VERSION 5.7 ;
  NOWIREEXTENSIONATPIN ON ;
  DIVIDERCHAR "/" ;
  BUSBITCHARS "[]" ;
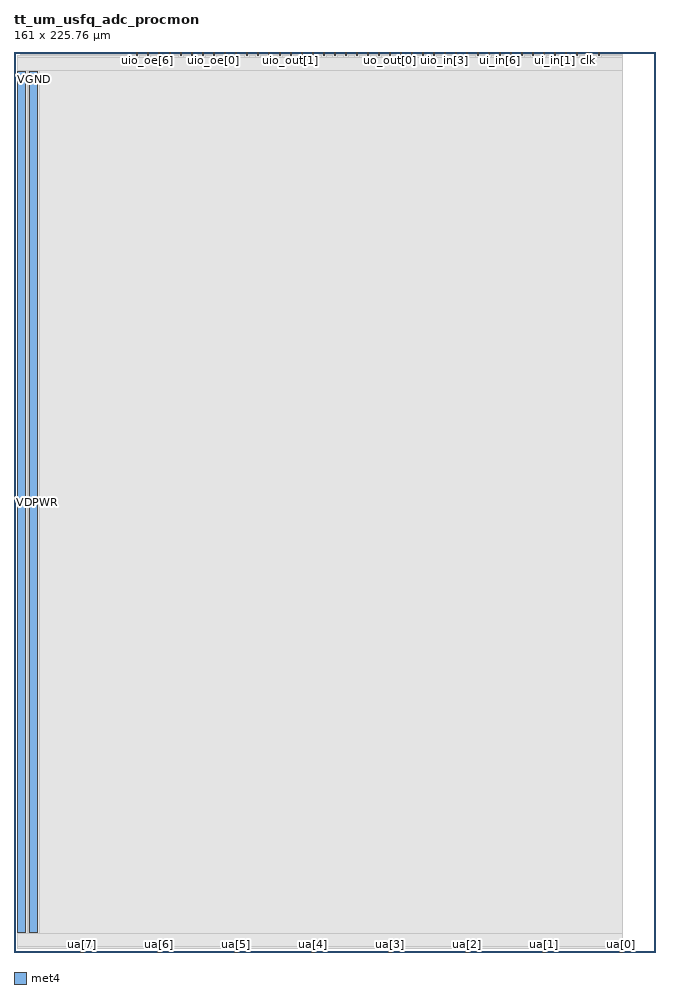
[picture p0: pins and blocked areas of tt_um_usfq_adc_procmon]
MACRO tt_um_usfq_adc_procmon
  CLASS BLOCK ;
  FOREIGN tt_um_usfq_adc_procmon ;
  ORIGIN 0.000 0.000 ;
  SIZE 161.000 BY 225.760 ;
  PIN VGND
    USE GROUND ;
    PORT
      LAYER met4 ;
        RECT 4.000 5.000 6.000 220.760 ;
    END
  END VGND
  PIN VDPWR
    USE POWER ;
    PORT
      LAYER met4 ;
        RECT 1.000 5.000 3.000 220.760 ;
    END
  END VDPWR
  PIN uo_out[7]
    ANTENNADIFFAREA 0.222600 ;
    PORT
      LAYER met4 ;
        RECT 74.830 224.760 75.130 225.760 ;
    END
  END uo_out[7]
  PIN uo_out[6]
    ANTENNADIFFAREA 0.222600 ;
    PORT
      LAYER met4 ;
        RECT 77.590 224.760 77.890 225.760 ;
    END
  END uo_out[6]
  PIN uo_out[5]
    ANTENNADIFFAREA 0.222600 ;
    PORT
      LAYER met4 ;
        RECT 80.350 224.760 80.650 225.760 ;
    END
  END uo_out[5]
  PIN uo_out[4]
    ANTENNADIFFAREA 0.222600 ;
    PORT
      LAYER met4 ;
        RECT 83.110 224.760 83.410 225.760 ;
    END
  END uo_out[4]
  PIN uo_out[3]
    ANTENNADIFFAREA 0.222600 ;
    PORT
      LAYER met4 ;
        RECT 85.870 224.760 86.170 225.760 ;
    END
  END uo_out[3]
  PIN uo_out[2]
    ANTENNADIFFAREA 0.222600 ;
    PORT
      LAYER met4 ;
        RECT 88.630 224.760 88.930 225.760 ;
    END
  END uo_out[2]
  PIN uo_out[1]
    PORT
      LAYER met4 ;
        RECT 91.390 224.760 91.690 225.760 ;
    END
  END uo_out[1]
  PIN uo_out[0]
    PORT
      LAYER met4 ;
        RECT 94.150 224.760 94.450 225.760 ;
    END
  END uo_out[0]
  PIN uio_out[7]
    ANTENNADIFFAREA 4.233600 ;
    PORT
      LAYER met4 ;
        RECT 52.750 224.760 53.050 225.760 ;
    END
  END uio_out[7]
  PIN uio_out[6]
    ANTENNADIFFAREA 4.233600 ;
    PORT
      LAYER met4 ;
        RECT 55.510 224.760 55.810 225.760 ;
    END
  END uio_out[6]
  PIN uio_out[5]
    ANTENNADIFFAREA 4.233600 ;
    PORT
      LAYER met4 ;
        RECT 58.270 224.760 58.570 225.760 ;
    END
  END uio_out[5]
  PIN uio_out[4]
    ANTENNADIFFAREA 4.233600 ;
    PORT
      LAYER met4 ;
        RECT 61.030 224.760 61.330 225.760 ;
    END
  END uio_out[4]
  PIN uio_out[3]
    ANTENNADIFFAREA 4.233600 ;
    PORT
      LAYER met4 ;
        RECT 63.790 224.760 64.090 225.760 ;
    END
  END uio_out[3]
  PIN uio_out[2]
    ANTENNADIFFAREA 4.233600 ;
    PORT
      LAYER met4 ;
        RECT 66.550 224.760 66.850 225.760 ;
    END
  END uio_out[2]
  PIN uio_out[1]
    ANTENNADIFFAREA 4.936500 ;
    PORT
      LAYER met4 ;
        RECT 69.310 224.760 69.610 225.760 ;
    END
  END uio_out[1]
  PIN uio_out[0]
    ANTENNADIFFAREA 4.233600 ;
    PORT
      LAYER met4 ;
        RECT 72.070 224.760 72.370 225.760 ;
    END
  END uio_out[0]
  PIN uio_oe[7]
    ANTENNAGATEAREA 32.830997 ;
    ANTENNADIFFAREA 174.069748 ;
    PORT
      LAYER met4 ;
        RECT 30.670 224.760 30.970 225.760 ;
    END
  END uio_oe[7]
  PIN uio_oe[6]
    ANTENNAGATEAREA 32.830997 ;
    ANTENNADIFFAREA 174.069748 ;
    PORT
      LAYER met4 ;
        RECT 33.430 224.760 33.730 225.760 ;
    END
  END uio_oe[6]
  PIN uio_oe[5]
    ANTENNAGATEAREA 32.830997 ;
    ANTENNADIFFAREA 174.069748 ;
    PORT
      LAYER met4 ;
        RECT 36.190 224.760 36.490 225.760 ;
    END
  END uio_oe[5]
  PIN uio_oe[4]
    ANTENNAGATEAREA 32.830997 ;
    ANTENNADIFFAREA 174.069748 ;
    PORT
      LAYER met4 ;
        RECT 38.950 224.760 39.250 225.760 ;
    END
  END uio_oe[4]
  PIN uio_oe[3]
    ANTENNAGATEAREA 32.830997 ;
    ANTENNADIFFAREA 174.069748 ;
    PORT
      LAYER met4 ;
        RECT 41.710 224.760 42.010 225.760 ;
    END
  END uio_oe[3]
  PIN uio_oe[2]
    ANTENNAGATEAREA 32.830997 ;
    ANTENNADIFFAREA 174.069748 ;
    PORT
      LAYER met4 ;
        RECT 44.470 224.760 44.770 225.760 ;
    END
  END uio_oe[2]
  PIN uio_oe[1]
    ANTENNAGATEAREA 32.830997 ;
    ANTENNADIFFAREA 174.069748 ;
    PORT
      LAYER met4 ;
        RECT 47.230 224.760 47.530 225.760 ;
    END
  END uio_oe[1]
  PIN uio_oe[0]
    ANTENNAGATEAREA 32.830997 ;
    ANTENNADIFFAREA 174.069748 ;
    PORT
      LAYER met4 ;
        RECT 49.990 224.760 50.290 225.760 ;
    END
  END uio_oe[0]
  PIN uio_in[7]
    PORT
      LAYER met4 ;
        RECT 96.910 224.760 97.210 225.760 ;
    END
  END uio_in[7]
  PIN uio_in[6]
    PORT
      LAYER met4 ;
        RECT 99.670 224.760 99.970 225.760 ;
    END
  END uio_in[6]
  PIN uio_in[5]
    PORT
      LAYER met4 ;
        RECT 102.430 224.760 102.730 225.760 ;
    END
  END uio_in[5]
  PIN uio_in[4]
    PORT
      LAYER met4 ;
        RECT 105.190 224.760 105.490 225.760 ;
    END
  END uio_in[4]
  PIN uio_in[3]
    PORT
      LAYER met4 ;
        RECT 107.950 224.760 108.250 225.760 ;
    END
  END uio_in[3]
  PIN uio_in[2]
    PORT
      LAYER met4 ;
        RECT 110.710 224.760 111.010 225.760 ;
    END
  END uio_in[2]
  PIN uio_in[1]
    PORT
      LAYER met4 ;
        RECT 113.470 224.760 113.770 225.760 ;
    END
  END uio_in[1]
  PIN uio_in[0]
    PORT
      LAYER met4 ;
        RECT 116.230 224.760 116.530 225.760 ;
    END
  END uio_in[0]
  PIN ui_in[7]
    ANTENNAGATEAREA 1.431000 ;
    PORT
      LAYER met4 ;
        RECT 118.990 224.760 119.290 225.760 ;
    END
  END ui_in[7]
  PIN ui_in[6]
    PORT
      LAYER met4 ;
        RECT 121.750 224.760 122.050 225.760 ;
    END
  END ui_in[6]
  PIN ui_in[5]
    PORT
      LAYER met4 ;
        RECT 124.510 224.760 124.810 225.760 ;
    END
  END ui_in[5]
  PIN ui_in[4]
    PORT
      LAYER met4 ;
        RECT 127.270 224.760 127.570 225.760 ;
    END
  END ui_in[4]
  PIN ui_in[3]
    PORT
      LAYER met4 ;
        RECT 130.030 224.760 130.330 225.760 ;
    END
  END ui_in[3]
  PIN ui_in[2]
    PORT
      LAYER met4 ;
        RECT 132.790 224.760 133.090 225.760 ;
    END
  END ui_in[2]
  PIN ui_in[1]
    PORT
      LAYER met4 ;
        RECT 135.550 224.760 135.850 225.760 ;
    END
  END ui_in[1]
  PIN ui_in[0]
    PORT
      LAYER met4 ;
        RECT 138.310 224.760 138.610 225.760 ;
    END
  END ui_in[0]
  PIN ua[7]
    PORT
      LAYER met4 ;
        RECT 16.570 0.000 17.470 1.000 ;
    END
  END ua[7]
  PIN ua[5]
    PORT
      LAYER met4 ;
        RECT 55.210 0.000 56.110 1.000 ;
    END
  END ua[5]
  PIN ua[4]
    PORT
      LAYER met4 ;
        RECT 74.530 0.000 75.430 1.000 ;
    END
  END ua[4]
  PIN ua[3]
    PORT
      LAYER met4 ;
        RECT 93.850 0.000 94.750 1.000 ;
    END
  END ua[3]
  PIN ua[2]
    PORT
      LAYER met4 ;
        RECT 113.170 0.000 114.070 1.000 ;
    END
  END ua[2]
  PIN ua[1]
    ANTENNAGATEAREA 15.929999 ;
    PORT
      LAYER met4 ;
        RECT 132.490 0.000 133.390 1.000 ;
    END
  END ua[1]
  PIN ua[0]
    ANTENNAGATEAREA 16.056000 ;
    PORT
      LAYER met4 ;
        RECT 151.810 0.000 152.710 1.000 ;
    END
  END ua[0]
  PIN rst_n
    PORT
      LAYER met4 ;
        RECT 141.070 224.760 141.370 225.760 ;
    END
  END rst_n
  PIN ena
    PORT
      LAYER met4 ;
        RECT 146.590 224.760 146.890 225.760 ;
    END
  END ena
  PIN clk
    PORT
      LAYER met4 ;
        RECT 143.830 224.760 144.130 225.760 ;
    END
  END clk
  PIN ua[6]
    PORT
      LAYER met4 ;
        RECT 35.890 0.000 36.790 1.000 ;
    END
  END ua[6]
  OBS
      LAYER nwell ;
        RECT 16.190 96.080 143.135 217.955 ;
      LAYER li1 ;
        RECT 16.320 96.210 143.005 217.775 ;
      LAYER met1 ;
        RECT 16.320 96.135 143.070 217.850 ;
      LAYER met2 ;
        RECT 1.680 1.385 152.610 225.015 ;
      LAYER met3 ;
        RECT 1.655 1.380 152.660 225.120 ;
      LAYER met4 ;
        RECT 1.000 224.360 30.270 225.000 ;
        RECT 31.370 224.360 33.030 225.000 ;
        RECT 34.130 224.360 35.790 225.000 ;
        RECT 36.890 224.360 38.550 225.000 ;
        RECT 39.650 224.360 41.310 225.000 ;
        RECT 42.410 224.360 44.070 225.000 ;
        RECT 45.170 224.360 46.830 225.000 ;
        RECT 47.930 224.360 49.590 225.000 ;
        RECT 50.690 224.360 52.350 225.000 ;
        RECT 53.450 224.360 55.110 225.000 ;
        RECT 56.210 224.360 57.870 225.000 ;
        RECT 58.970 224.360 60.630 225.000 ;
        RECT 61.730 224.360 63.390 225.000 ;
        RECT 64.490 224.360 66.150 225.000 ;
        RECT 67.250 224.360 68.910 225.000 ;
        RECT 70.010 224.360 71.670 225.000 ;
        RECT 72.770 224.360 74.430 225.000 ;
        RECT 75.530 224.360 77.190 225.000 ;
        RECT 78.290 224.360 79.950 225.000 ;
        RECT 81.050 224.360 82.710 225.000 ;
        RECT 83.810 224.360 85.470 225.000 ;
        RECT 86.570 224.360 88.230 225.000 ;
        RECT 89.330 224.360 90.990 225.000 ;
        RECT 92.090 224.360 93.750 225.000 ;
        RECT 94.850 224.360 96.510 225.000 ;
        RECT 97.610 224.360 99.270 225.000 ;
        RECT 100.370 224.360 102.030 225.000 ;
        RECT 103.130 224.360 104.790 225.000 ;
        RECT 105.890 224.360 107.550 225.000 ;
        RECT 108.650 224.360 110.310 225.000 ;
        RECT 111.410 224.360 113.070 225.000 ;
        RECT 114.170 224.360 115.830 225.000 ;
        RECT 116.930 224.360 118.590 225.000 ;
        RECT 119.690 224.360 121.350 225.000 ;
        RECT 122.450 224.360 124.110 225.000 ;
        RECT 125.210 224.360 126.870 225.000 ;
        RECT 127.970 224.360 129.630 225.000 ;
        RECT 130.730 224.360 132.390 225.000 ;
        RECT 133.490 224.360 135.150 225.000 ;
        RECT 136.250 224.360 137.910 225.000 ;
        RECT 139.010 224.360 140.670 225.000 ;
        RECT 141.770 224.360 143.430 225.000 ;
        RECT 144.530 224.360 146.190 225.000 ;
        RECT 147.290 224.360 152.710 225.000 ;
        RECT 1.000 221.160 152.710 224.360 ;
        RECT 1.000 220.760 3.000 221.160 ;
        RECT 3.400 4.600 3.600 221.160 ;
        RECT 6.400 4.600 152.710 221.160 ;
        RECT 1.000 1.400 152.710 4.600 ;
        RECT 1.000 1.000 16.170 1.400 ;
        RECT 17.870 1.000 35.490 1.400 ;
        RECT 37.190 1.000 54.810 1.400 ;
        RECT 56.510 1.000 74.130 1.400 ;
        RECT 75.830 1.000 93.450 1.400 ;
        RECT 95.150 1.000 112.770 1.400 ;
        RECT 114.470 1.000 132.090 1.400 ;
        RECT 133.790 1.000 151.410 1.400 ;
  END
END tt_um_usfq_adc_procmon
END LIBRARY

